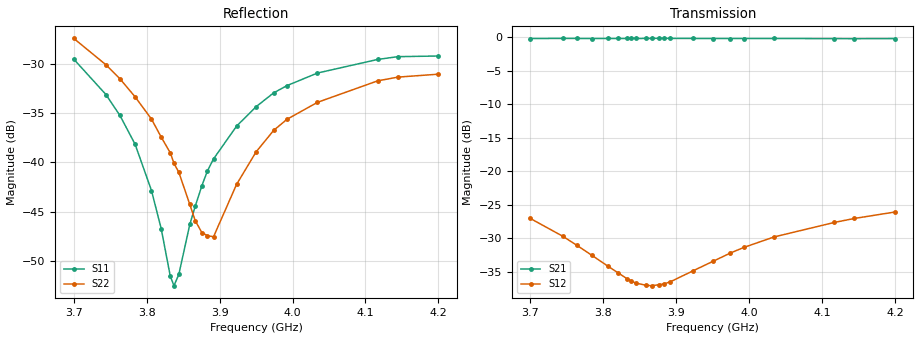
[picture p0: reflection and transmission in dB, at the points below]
! MS46524B
! 12345/M1: Not Set/M2: Not Set
! 3/11/2021 9:23:22 PM
! D:\WEBSITE FILES\DATASHEETS\MEASURED DATA\3.7-4.2 GHZ (D4I3742).S2P
! CHANNEL.1
! TR.MEASUREMENT
! RAW.DATA
# GHZ S RI R 50.0
! FREQ.GHZ  S11RE  S11IM  S21RE  S21IM  S12RE  S12IM  S22RE  S22IM
!; PortSelection: Port_12
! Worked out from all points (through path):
!   601 points, 3.7 GHz to 4.2 GHz, reference 50 ohm
!   highest |S21| = -0.15 dB at 3.883 GHz (marker M1); lowest = -0.2 dB at 4.144 GHz (marker M2)
!   lowest |S11| = -52.5 dB at 3.837 GHz (marker M3), VSWR 1.00, Z = 50.2 + j0.0413 ohm
!   |S11| at or under -10 dB: start of sweep to end of sweep
!   |S22| runs from -47.9 to -27.4 dB; largest |S21 - S12| = 1
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3.7  0.0163 -0.0294  0.741 -0.6416  -0.0445 -0.00232  0.0223 -0.0366
3.744167  0.0102 -0.0197  0.6665 -0.7208  -0.0329 0.000286  0.0156 -0.0273
3.763333  0.00802 -0.0154  0.6296 -0.7526  -0.0282 7.58e-05  0.0132 -0.0232
3.784167  0.00623 -0.0107  0.5883 -0.7834  -0.0237 -0.000295  0.0108 -0.0187
3.806667  0.00437 -0.00571  0.5429 -0.8167  -0.0195 -0.00182  0.00911 -0.0139
3.82  0.00342 -0.00307  0.5151 -0.8344  -0.0173 -0.00293  0.00775 -0.011
3.8325  0.00258 -0.000482  0.4892 -0.8503  -0.0153 -0.00413  0.00714 -0.0086
3.8375  0.00232 0.000411  0.4786 -0.8561  -0.0146 -0.0047  0.00655 -0.00742
3.844167  0.00201 0.00179  0.4639 -0.8638  -0.0137 -0.00538  0.00627 -0.00631
3.859167  0.00128 0.00466  0.4301 -0.8822  -0.0122 -0.00711  0.00512 -0.00334
3.866667  0.00107 0.00589  0.4131 -0.8911  -0.0115 -0.00807  0.0046 -0.00208
3.875833  0.000762 0.00759  0.3921 -0.9009  -0.0108 -0.00934  0.00435 -0.00053
3.883333  0.000855 0.00901  0.3745 -0.9084  -0.0102 -0.0103  0.00419 0.000642
3.891667  0.000591 0.0104  0.3547 -0.9161  -0.00998 -0.0112  0.00367 0.002
3.923333  0.000702 0.0153  0.2786 -0.9406  -0.00932 -0.0156  0.00318 0.00705
3.95  0.000742 0.0192  0.2138 -0.9567  -0.00983 -0.0189  0.00302 0.0109
3.974167  0.00103 0.0226  0.1548 -0.9669  -0.0114 -0.0218  0.00279 0.0143
3.9925  0.00122 0.0246  0.1097 -0.9737  -0.0133 -0.0236  0.00255 0.0164
4.034167  0.00143 0.0285  0.00457 -0.9804  -0.0186 -0.0266  0.00235 0.0201
4.116667  0.00335 0.0333  -0.2048 -0.9565  -0.0332 -0.0251  0.00266 0.0259
4.144167  0.00347 0.0344  -0.2724 -0.9384  -0.0386 -0.0223  0.0023 0.0271
4.2  0.00322 0.0347  -0.4079 -0.8904  -0.0483 -0.0122  0.00183 0.0281
